VERSION 5.8 ;
BUSBITCHARS "[]" ;
DIVIDERCHAR "/" ;

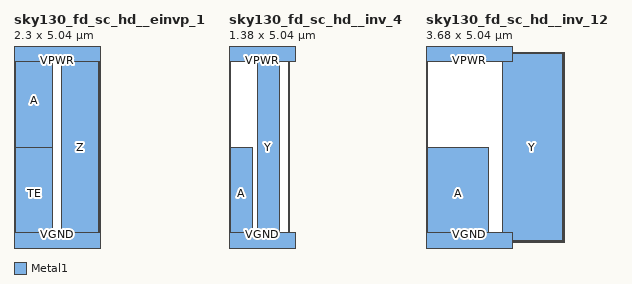
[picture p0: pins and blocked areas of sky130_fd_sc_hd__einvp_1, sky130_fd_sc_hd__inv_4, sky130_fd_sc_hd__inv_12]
MACRO sky130_fd_sc_hd__einvp_1
  CLASS CORE ;
  FOREIGN sky130_fd_sc_hd__einvp_1 ;
  ORIGIN 0 0 ;
  SIZE 2.3 BY 5.04 ;
  SYMMETRY X Y R90 ;
  SITE GF018hv5v_green_sc9 ;
  PIN A
    DIRECTION INPUT ;  USE SIGNAL ;
    PORT  LAYER Metal1 ;  RECT 0.05 2.52 1.03 4.99 ;  END
  END A
  PIN TE
    DIRECTION INPUT ;  USE SIGNAL ;
    PORT  LAYER Metal1 ;  RECT 0.05 0.05 1.03 2.52 ;  END
  END TE
  PIN Z
    DIRECTION OUTPUT ;  USE SIGNAL ;
    PORT  LAYER Metal1 ;  RECT 1.26 0.05 2.25 4.99 ;  END
  END Z
  PIN VPWR
    DIRECTION INOUT ;  USE POWER ;  SHAPE ABUTMENT ;
    PORT  LAYER Metal1 ;  RECT 0 4.80 2.30 5.28 ;  END
  END VPWR
  PIN VGND
    DIRECTION INOUT ;  USE GROUND ;  SHAPE ABUTMENT ;
    PORT  LAYER Metal1 ;  RECT 0 -0.24 2.30 0.24 ;  END
  END VGND
END sky130_fd_sc_hd__einvp_1

MACRO sky130_fd_sc_hd__inv_4
  CLASS CORE ;
  FOREIGN sky130_fd_sc_hd__inv_4 ;
  ORIGIN 0 0 ;
  SIZE 1.38 BY 5.04 ;
  SYMMETRY X Y R90 ;
  SITE GF018hv5v_green_sc9 ;
  PIN A
    DIRECTION INPUT ;  USE SIGNAL ;
    PORT  LAYER Metal1 ;  RECT 0.05 0.05 0.62 2.52 ;  END
  END A
  PIN Y
    DIRECTION OUTPUT ;  USE SIGNAL ;
    PORT  LAYER Metal1 ;  RECT 0.76 0.05 1.33 4.99 ;  END
  END Y
  PIN VPWR
    DIRECTION INOUT ;  USE POWER ;  SHAPE ABUTMENT ;
    PORT  LAYER Metal1 ;  RECT 0 4.80 2.30 5.28 ;  END
  END VPWR
  PIN VGND
    DIRECTION INOUT ;  USE GROUND ;  SHAPE ABUTMENT ;
    PORT  LAYER Metal1 ;  RECT 0 -0.24 2.30 0.24 ;  END
  END VGND
END sky130_fd_sc_hd__inv_4

MACRO sky130_fd_sc_hd__inv_12
  CLASS CORE ;
  FOREIGN sky130_fd_sc_hd__inv_12 ;
  ORIGIN 0 0 ;
  SIZE 3.68 BY 5.04 ;
  SYMMETRY X Y R90 ;
  SITE GF018hv5v_green_sc9 ;
  PIN A
    DIRECTION INPUT ;  USE SIGNAL ;
    PORT  LAYER Metal1 ;  RECT 0.05 0.05 1.66 2.52 ;  END
  END A
  PIN Y
    DIRECTION OUTPUT ;  USE SIGNAL ;
    PORT  LAYER Metal1 ;  RECT 2.02 0.05 3.63 4.99 ;  END
  END Y
  PIN VPWR
    DIRECTION INOUT ;  USE POWER ;  SHAPE ABUTMENT ;
    PORT  LAYER Metal1 ;  RECT 0 4.80 2.30 5.28 ;  END
  END VPWR
  PIN VGND
    DIRECTION INOUT ;  USE GROUND ;  SHAPE ABUTMENT ;
    PORT  LAYER Metal1 ;  RECT 0 -0.24 2.30 0.24 ;  END
  END VGND
END sky130_fd_sc_hd__inv_12

END LIBRARY
